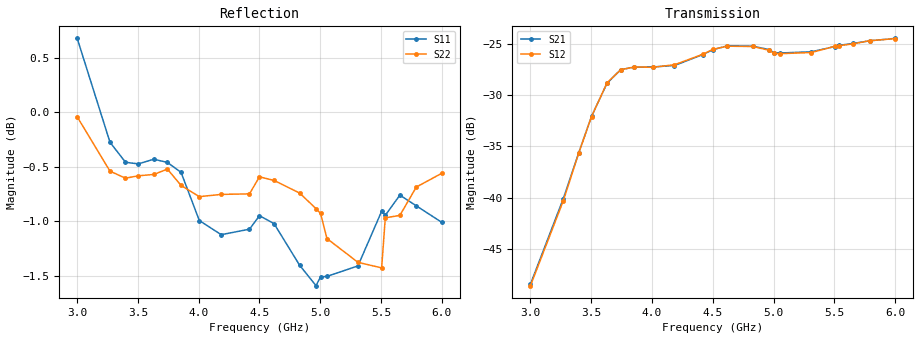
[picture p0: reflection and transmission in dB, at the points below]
!  26/11/2025  16:11:02
! Ref Plane: 0.000 mm
# MHZ S MA R  50
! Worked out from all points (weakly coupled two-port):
!   401 points, 3 GHz to 6 GHz, reference 50 ohm
!   highest |S21| = -24.46 dB at 6 GHz (marker M1); lowest = -48.5 dB at 3 GHz (marker M2)
!   lowest |S11| = -1.6 dB at 4.965 GHz (marker M3), VSWR 10.93, Z = 9.67 - j52.3 ohm
!   |S11| at or under -10 dB: nowhere
!   |S22| runs from -1.4 to 0.0 dB; largest |S21 - S12| = 0.0025
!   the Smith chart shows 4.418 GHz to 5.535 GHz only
!   S11 on the Smith chart (normalised r, x): 4.418 GHz: 0.12, +0.99; 4.62 GHz: 1.29, +4.40; 4.83 GHz: 0.56, -2.37; 5.055 GHz: 0.12, -0.66; 5.31 GHz: 0.08, +0.02; 5.535 GHz: 0.08, +0.65
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3000  1.081 -138.0  0.00378 48.0  0.003714 50.4  0.995 -105.9
3270  0.9686 151.8  0.009874 -18.5  0.009636 -15.5  0.9395 -170.7
3397.5  0.9484 108.8  0.01657 -58.3  0.0165 -57.3  0.9325 150.5
3502.5  0.9467 66.0  0.02493 -98.6  0.02485 -97.4  0.9349 112.6
3630  0.9514 10.8  0.03609 -154.5  0.0363 -153.1  0.9362 57.8
3742.5  0.9482 -39.3  0.04207 155.5  0.04206 157.1  0.9415 9.7
3855  0.9382 -84.9  0.04331 109.2  0.04338 110.8  0.9254 -36.3
4005  0.8917 -138.9  0.04337 55.7  0.0432 56.9  0.9145 -88.5
4185  0.8785 164.1  0.04409 -0.8  0.04446 1.3  0.9167 -145.2
4417.5  0.8836 90.1  0.04985 -71.3  0.05001 -69.6  0.9172 143.7
4500  0.8963 63.7  0.05264 -97.8  0.05284 -96.3  0.9339 118.4
4620  0.8888 23.7  0.055 -137.1  0.05478 -135.8  0.9303 80.7
4830  0.8506 -43.8  0.05477 155.4  0.05459 157.1  0.918 17.8
4965  0.8324 -86.4  0.05271 115.3  0.05231 116.8  0.903 -21.0
5002.5  0.8402 -97.8  0.05092 104.9  0.05048 106.2  0.8984 -32.8
5055  0.8406 -112.6  0.05075 90.1  0.05037 91.0  0.8749 -48.6
5310  0.85 177.9  0.05143 22.1  0.05101 23.6  0.8532 -122.4
5505  0.9005 120.6  0.05455 -31.4  0.05471 -29.5  0.8482 -174.5
5535  0.8966 113.9  0.05527 -38.9  0.05507 -36.8  0.8943 179.0
5655  0.916 79.3  0.0565 -73.3  0.05622 -70.9  0.8966 143.8
5790  0.9057 40.3  0.05817 -112.5  0.05826 -110.4  0.9238 105.9
6000  0.89 -21.4  0.05981 -172.9  0.05963 -171.3  0.9374 52.0
